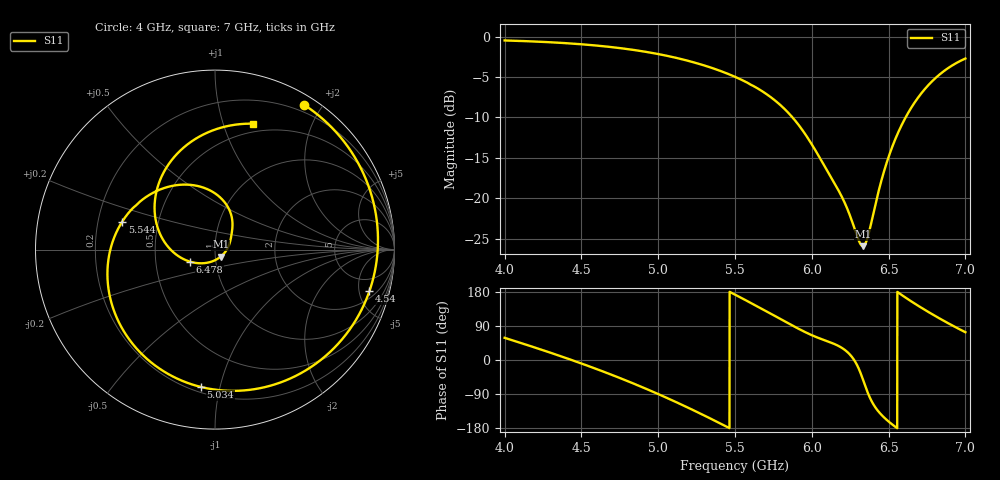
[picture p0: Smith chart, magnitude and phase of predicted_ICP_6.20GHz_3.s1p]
! ICP-predicted S11, target max centred GHz at -10 dB. Complex ensemble mean (passive and causal);
! its |S11| can differ slightly from the dB-domain mean reported in designs.csv.
!  Air_gap = 3.33mm
!  W_Patch = 16.59mm
!  L_Patch = 15.49mm
!  Sx = 2.74mm
!  Sy = 4.74mm
!  W_Patch1 = 13.03mm
!  WS = 0.89mm
!  Curve_Amp1 = 0.63mm
!  Extra = 1.38mm
# GHz S MA R 50
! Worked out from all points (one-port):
!   3001 points, 4 GHz to 7 GHz, reference 50 ohm
!   lowest |S11| = -25.9 dB at 6.333 GHz (marker M1), VSWR 1.11, Z = 53.1 - j4.2 ohm
!   |S11| at or under -10 dB: 5.875 GHz to 6.611 GHz (736.2 MHz wide, 11.8 % of centre)
!   S11 on the Smith chart (normalised r, x): 4 GHz: 0.11, +1.78; 4.54 GHz: 2.82, -6.33; 5.034 GHz: 0.23, -0.87; 5.544 GHz: 0.30, +0.13; 6.478 GHz: 0.75, -0.10; 7 GHz: 0.42, +1.26
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4  0.9474 58.6
4.203  0.9326 32.1
4.375  0.9145 8.7
4.54  0.8909 -15.1
4.643  0.8725 -30.6
4.75  0.8499 -47.5
4.896  0.8123 -71.7
5.034  0.7691 -95.9
5.125  0.7363 -112.7
5.226  0.6957 -131.9
5.319  0.6548 -150.2
5.409  0.6116 -168.5
5.5  0.5643 172.6
5.544  0.54 163.2
5.71  0.4378 127.2
5.789  0.3821 109.6
5.875  0.3158 90.7
6.014  0.2049 63.0
6.25  0.07744 13.6
6.333  0.05051 -51.5
6.366  0.05828 -88.0
6.478  0.1553 -154.5
6.55  0.2399 -178.2
6.625  0.3345 160.7
6.708  0.4396 139.3
6.79  0.5373 119.3
6.9  0.6506 94.4
7  0.7325 73.3
